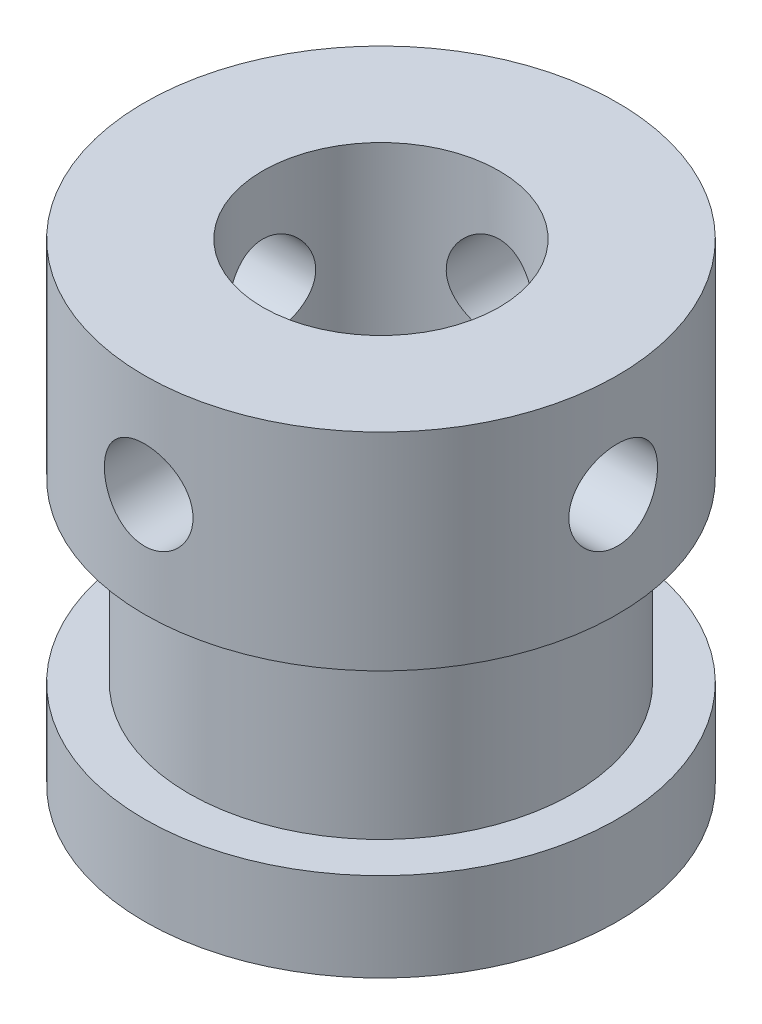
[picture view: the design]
ISO-10303-21;
HEADER;
FILE_DESCRIPTION(('STEP AP214'),'2;1');
FILE_NAME('part.step','',(''),(''),'','','');
FILE_SCHEMA(('AUTOMOTIVE_DESIGN { 1 0 10303 214 1 1 1 1 }'));
ENDSEC;
DATA;
#1=APPLICATION_CONTEXT('core data for automotive mechanical design processes');
#2=APPLICATION_PROTOCOL_DEFINITION('international standard','automotive_design',2000,#1);
#3=PRODUCT_CONTEXT('',#1,'mechanical');
#4=PRODUCT('Part','Part','',(#3));
#5=PRODUCT_RELATED_PRODUCT_CATEGORY('part','',(#4));
#6=PRODUCT_DEFINITION_FORMATION('','',#4);
#7=PRODUCT_DEFINITION_CONTEXT('part definition',#1,'design');
#8=PRODUCT_DEFINITION('design','',#6,#7);
#9=PRODUCT_DEFINITION_SHAPE('','',#8);
#10=(LENGTH_UNIT() NAMED_UNIT(*) SI_UNIT(.MILLI.,.METRE.));
#11=(NAMED_UNIT(*) PLANE_ANGLE_UNIT() SI_UNIT($,.RADIAN.));
#12=(NAMED_UNIT(*) SI_UNIT($,.STERADIAN.) SOLID_ANGLE_UNIT());
#13=UNCERTAINTY_MEASURE_WITH_UNIT(LENGTH_MEASURE(1.E-05),#10,'distance_accuracy_value','');
#14=(GEOMETRIC_REPRESENTATION_CONTEXT(3) GLOBAL_UNCERTAINTY_ASSIGNED_CONTEXT((#13)) GLOBAL_UNIT_ASSIGNED_CONTEXT((#10,
#11,#12)) REPRESENTATION_CONTEXT('',''));
#15=CARTESIAN_POINT('',(0.,0.,0.));
#16=DIRECTION('',(0.,0.,1.));
#17=DIRECTION('',(1.,0.,0.));
#18=AXIS2_PLACEMENT_3D('',#15,#16,#17);
#19=CARTESIAN_POINT('',(0.,16.,0.));
#20=DIRECTION('',(0.,-1.,0.));
#21=DIRECTION('',(0.,0.,-1.));
#22=AXIS2_PLACEMENT_3D('',#19,#20,#21);
#23=CYLINDRICAL_SURFACE('',#22,8.);
#24=CARTESIAN_POINT('',(0.,0.,0.));
#25=DIRECTION('',(0.,1.,0.));
#26=DIRECTION('',(0.,0.,1.));
#27=AXIS2_PLACEMENT_3D('',#24,#25,#26);
#28=CIRCLE('',#27,8.);
#29=CARTESIAN_POINT('',(0.,0.,8.));
#30=VERTEX_POINT('',#29);
#31=EDGE_CURVE('E57',#30,#30,#28,.T.);
#32=ORIENTED_EDGE('',*,*,#31,.T.);
#33=EDGE_LOOP('',(#32));
#34=FACE_BOUND('',#33,.T.);
#35=CARTESIAN_POINT('',(0.,3.,0.));
#36=DIRECTION('',(0.,1.,0.));
#37=DIRECTION('',(0.,0.,1.));
#38=AXIS2_PLACEMENT_3D('',#35,#36,#37);
#39=CIRCLE('',#38,8.);
#40=CARTESIAN_POINT('',(0.,3.,8.));
#41=VERTEX_POINT('',#40);
#42=EDGE_CURVE('E70',#41,#41,#39,.T.);
#43=ORIENTED_EDGE('',*,*,#42,.F.);
#44=EDGE_LOOP('',(#43));
#45=FACE_BOUND('',#44,.T.);
#46=ADVANCED_FACE('F45',(#34,#45),#23,.T.);
#47=CARTESIAN_POINT('',(0.,14.,-8.));
#48=CARTESIAN_POINT('',(-0.0834717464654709,13.9999968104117,-7.99999848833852));
#49=CARTESIAN_POINT('',(-0.166984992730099,13.9930089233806,-7.99868009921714));
#50=CARTESIAN_POINT('',(-0.331658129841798,13.9652600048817,-7.9935478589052));
#51=CARTESIAN_POINT('',(-0.412815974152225,13.9444873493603,-7.98973190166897));
#52=CARTESIAN_POINT('',(-0.570372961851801,13.8898272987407,-7.98003138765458));
#53=CARTESIAN_POINT('',(-0.646776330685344,13.8559517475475,-7.97414869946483));
#54=CARTESIAN_POINT('',(-0.792807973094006,13.7760811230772,-7.96095710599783));
#55=CARTESIAN_POINT('',(-0.862436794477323,13.7300870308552,-7.9536483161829));
#56=CARTESIAN_POINT('',(-0.993783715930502,13.6267002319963,-7.93831336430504));
#57=CARTESIAN_POINT('',(-1.05540895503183,13.5691905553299,-7.93028034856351));
#58=CARTESIAN_POINT('',(-1.16819606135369,13.4446566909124,-7.9144531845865));
#59=CARTESIAN_POINT('',(-1.21935717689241,13.3776318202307,-7.90665905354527));
#60=CARTESIAN_POINT('',(-1.31014998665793,13.235313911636,-7.89212551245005));
#61=CARTESIAN_POINT('',(-1.34968721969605,13.1599596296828,-7.88539493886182));
#62=CARTESIAN_POINT('',(-1.41550524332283,13.0035310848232,-7.87384713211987));
#63=CARTESIAN_POINT('',(-1.44178717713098,12.9224573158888,-7.86902973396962));
#64=CARTESIAN_POINT('',(-1.480050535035,12.7578847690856,-7.8619226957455));
#65=CARTESIAN_POINT('',(-1.49219390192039,12.6744249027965,-7.85960445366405));
#66=CARTESIAN_POINT('',(-1.50233808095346,12.5066226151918,-7.85767197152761));
#67=CARTESIAN_POINT('',(-1.50034016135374,12.4222802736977,-7.8580574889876));
#68=CARTESIAN_POINT('',(-1.48238979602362,12.256280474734,-7.86146292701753));
#69=CARTESIAN_POINT('',(-1.46662149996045,12.1746022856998,-7.86444808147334));
#70=CARTESIAN_POINT('',(-1.42186799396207,12.0150715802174,-7.87266183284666));
#71=CARTESIAN_POINT('',(-1.39288222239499,11.9372192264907,-7.87789052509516));
#72=CARTESIAN_POINT('',(-1.322336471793,11.7870113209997,-7.89003855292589));
#73=CARTESIAN_POINT('',(-1.28070213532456,11.7146915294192,-7.89696783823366));
#74=CARTESIAN_POINT('',(-1.18609368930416,11.5779952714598,-7.91172971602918));
#75=CARTESIAN_POINT('',(-1.13311842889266,11.5136196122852,-7.91956240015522));
#76=CARTESIAN_POINT('',(-1.01633905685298,11.3935750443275,-7.93540001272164));
#77=CARTESIAN_POINT('',(-0.952377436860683,11.3380593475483,-7.94340571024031));
#78=CARTESIAN_POINT('',(-0.815968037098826,11.2385227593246,-7.95857386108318));
#79=CARTESIAN_POINT('',(-0.743520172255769,11.1945019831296,-7.96573630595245));
#80=CARTESIAN_POINT('',(-0.592034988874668,11.11918224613,-7.97842539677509));
#81=CARTESIAN_POINT('',(-0.512989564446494,11.0878992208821,-7.98394999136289));
#82=CARTESIAN_POINT('',(-0.350639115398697,11.0390979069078,-7.99272505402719));
#83=CARTESIAN_POINT('',(-0.267334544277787,11.0215781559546,-7.99597576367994));
#84=CARTESIAN_POINT('',(-0.100148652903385,11.0010139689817,-7.99980360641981));
#85=CARTESIAN_POINT('',(-0.0162940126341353,10.9977596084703,-8.00041950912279));
#86=CARTESIAN_POINT('',(0.150761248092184,11.0052554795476,-7.99901543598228));
#87=CARTESIAN_POINT('',(0.233961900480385,11.0160050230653,-7.99699558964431));
#88=CARTESIAN_POINT('',(0.396681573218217,11.0510290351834,-7.99057111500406));
#89=CARTESIAN_POINT('',(0.476224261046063,11.0751972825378,-7.98618522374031));
#90=CARTESIAN_POINT('',(0.630128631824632,11.1362577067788,-7.97551842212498));
#91=CARTESIAN_POINT('',(0.704489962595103,11.1731507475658,-7.96923738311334));
#92=CARTESIAN_POINT('',(0.846816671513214,11.2590781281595,-7.95538030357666));
#93=CARTESIAN_POINT('',(0.914703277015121,11.3082407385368,-7.94779086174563));
#94=CARTESIAN_POINT('',(1.04133832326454,11.4171381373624,-7.93219343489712));
#95=CARTESIAN_POINT('',(1.10008590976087,11.4768739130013,-7.92418541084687));
#96=CARTESIAN_POINT('',(1.20757295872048,11.6061723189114,-7.9085247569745));
#97=CARTESIAN_POINT('',(1.25616916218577,11.6758549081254,-7.90087825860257));
#98=CARTESIAN_POINT('',(1.34096675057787,11.8225176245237,-7.88692985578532));
#99=CARTESIAN_POINT('',(1.37716859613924,11.8994974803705,-7.8806279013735));
#100=CARTESIAN_POINT('',(1.43594673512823,12.0582058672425,-7.87013024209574));
#101=CARTESIAN_POINT('',(1.45858868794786,12.1399093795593,-7.86592440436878));
#102=CARTESIAN_POINT('',(1.48980679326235,12.3060472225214,-7.86007203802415));
#103=CARTESIAN_POINT('',(1.49838453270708,12.3904812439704,-7.8584252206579));
#104=CARTESIAN_POINT('',(1.50117762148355,12.5582483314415,-7.85789199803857));
#105=CARTESIAN_POINT('',(1.49561895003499,12.641577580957,-7.85896215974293));
#106=CARTESIAN_POINT('',(1.47079175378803,12.8060914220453,-7.86364600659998));
#107=CARTESIAN_POINT('',(1.45152331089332,12.8872760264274,-7.86725967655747));
#108=CARTESIAN_POINT('',(1.39991887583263,13.0450744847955,-7.8766050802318));
#109=CARTESIAN_POINT('',(1.36760735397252,13.1216965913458,-7.88233284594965));
#110=CARTESIAN_POINT('',(1.29085868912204,13.2684682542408,-7.8952638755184));
#111=CARTESIAN_POINT('',(1.24642068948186,13.3386173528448,-7.90246724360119));
#112=CARTESIAN_POINT('',(1.14589487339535,13.4715836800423,-7.91767266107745));
#113=CARTESIAN_POINT('',(1.08964259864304,13.5342754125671,-7.92568505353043));
#114=CARTESIAN_POINT('',(0.967427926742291,13.6494051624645,-7.94152833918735));
#115=CARTESIAN_POINT('',(0.901463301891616,13.7018408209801,-7.94935919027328));
#116=CARTESIAN_POINT('',(0.760984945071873,13.7954109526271,-7.96403975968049));
#117=CARTESIAN_POINT('',(0.686399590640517,13.8364394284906,-7.97088000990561));
#118=CARTESIAN_POINT('',(0.531290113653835,13.9053176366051,-7.98271619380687));
#119=CARTESIAN_POINT('',(0.450771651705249,13.9331797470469,-7.98771385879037));
#120=CARTESIAN_POINT('',(0.308347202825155,13.9692773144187,-7.99428290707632));
#121=CARTESIAN_POINT('',(0.247273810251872,13.9807786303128,-7.99641470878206));
#122=CARTESIAN_POINT('',(0.124141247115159,13.9961410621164,-7.9992737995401));
#123=CARTESIAN_POINT('',(0.06208210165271,14.0000023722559,-8.00000112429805));
#124=CARTESIAN_POINT('',(0.,14.,-8.));
#125=B_SPLINE_CURVE_WITH_KNOTS('',3,(#47,#48,#49,#50,#51,#52,#53,#54,#55,#56,#57,#58,#59,#60,
#61,#62,#63,#64,#65,#66,#67,#68,#69,#70,#71,#72,#73,#74,#75,#76,#77,#78,#79,#80,#81,#82,#83,#84,
#85,#86,#87,#88,#89,#90,#91,#92,#93,#94,#95,#96,#97,#98,#99,#100,#101,#102,#103,#104,#105,#106,
#107,#108,#109,#110,#111,#112,#113,#114,#115,#116,#117,#118,#119,#120,#121,#122,#123,#124),
.UNSPECIFIED.,.T.,.F.,(4,2,2,2,2,2,2,2,2,2,2,2,2,2,2,2,2,2,2,2,2,2,2,2,2,2,2,2,2,2,2,2,2,2,2,2,
2,2,4),(0.,0.250188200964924,0.500587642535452,0.750761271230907,1.00091465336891,
1.2537511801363,1.50660586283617,1.76146190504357,2.01629596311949,2.26818151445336,
2.52004447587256,2.76859000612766,3.01714609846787,3.26719262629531,3.51726454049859,
3.77127768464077,4.02529337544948,4.27962588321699,4.53393136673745,4.78448174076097,
5.03501980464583,5.28360233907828,5.53220175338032,5.78351778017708,6.03485728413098,
6.28953436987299,6.54420198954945,6.79762627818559,7.05102196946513,7.30039252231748,
7.54976158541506,7.79866496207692,8.04758592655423,8.3002336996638,8.55293951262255,
8.80792048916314,9.06266126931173,9.24874344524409,9.43482089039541),.UNSPECIFIED.);
#126=CARTESIAN_POINT('',(0.,14.,-8.));
#127=VERTEX_POINT('',#126);
#128=EDGE_CURVE('E81',#127,#127,#125,.T.);
#129=ORIENTED_EDGE('',*,*,#128,.T.);
#130=EDGE_LOOP('',(#129));
#131=FACE_BOUND('',#130,.T.);
#132=CARTESIAN_POINT('',(1.5,12.5,7.85811682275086));
#133=CARTESIAN_POINT('',(1.49999679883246,12.4165427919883,7.85811843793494));
#134=CARTESIAN_POINT('',(1.49301126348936,12.3330440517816,7.85946079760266));
#135=CARTESIAN_POINT('',(1.46527253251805,12.1684010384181,7.86467851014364));
#136=CARTESIAN_POINT('',(1.44450765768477,12.0872588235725,7.86855601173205));
#137=CARTESIAN_POINT('',(1.38987035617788,11.9297349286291,7.87838976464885));
#138=CARTESIAN_POINT('',(1.35601013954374,11.8533488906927,7.88434407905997));
#139=CARTESIAN_POINT('',(1.27617565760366,11.7073464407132,7.89765826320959));
#140=CARTESIAN_POINT('',(1.23020233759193,11.6377295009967,7.90501802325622));
#141=CARTESIAN_POINT('',(1.12683678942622,11.5063698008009,7.92041614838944));
#142=CARTESIAN_POINT('',(1.06932292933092,11.4447235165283,7.92846116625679));
#143=CARTESIAN_POINT('',(0.944771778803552,11.3318956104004,7.94426457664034));
#144=CARTESIAN_POINT('',(0.877733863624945,11.2807146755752,7.95202295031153));
#145=CARTESIAN_POINT('',(0.735403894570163,11.1899006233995,7.96645017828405));
#146=CARTESIAN_POINT('',(0.660052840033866,11.1503584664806,7.97311028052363));
#147=CARTESIAN_POINT('',(0.503631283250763,11.0845304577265,7.98451608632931));
#148=CARTESIAN_POINT('',(0.422561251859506,11.0582435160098,7.98926194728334));
#149=CARTESIAN_POINT('',(0.258002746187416,11.0199704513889,7.99625755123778));
#150=CARTESIAN_POINT('',(0.174553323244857,11.0078216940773,7.99853565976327));
#151=CARTESIAN_POINT('',(0.00677167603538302,10.9976631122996,8.00043684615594));
#152=CARTESIAN_POINT('',(-0.0775604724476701,10.9996520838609,8.00006015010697));
#153=CARTESIAN_POINT('',(-0.243598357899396,11.0175877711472,7.99671633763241));
#154=CARTESIAN_POINT('',(-0.325323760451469,11.03335936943,7.99378172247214));
#155=CARTESIAN_POINT('',(-0.484947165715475,11.0781356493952,7.98568826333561));
#156=CARTESIAN_POINT('',(-0.56284502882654,11.1071408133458,7.98052933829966));
#157=CARTESIAN_POINT('',(-0.71311006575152,11.1777277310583,7.96851260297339));
#158=CARTESIAN_POINT('',(-0.785443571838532,11.2193794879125,7.96164537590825));
#159=CARTESIAN_POINT('',(-0.922159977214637,11.3140256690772,7.9469714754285));
#160=CARTESIAN_POINT('',(-0.986542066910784,11.3670212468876,7.93916470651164));
#161=CARTESIAN_POINT('',(-1.10656561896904,11.4838157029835,7.92333513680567));
#162=CARTESIAN_POINT('',(-1.16205790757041,11.5477677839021,7.91531085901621));
#163=CARTESIAN_POINT('',(-1.2615517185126,11.6841495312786,7.90006508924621));
#164=CARTESIAN_POINT('',(-1.30555307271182,11.7565793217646,7.89284360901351));
#165=CARTESIAN_POINT('',(-1.38085852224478,11.9080582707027,7.88001893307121));
#166=CARTESIAN_POINT('',(-1.41214093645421,11.9871184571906,7.87441850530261));
#167=CARTESIAN_POINT('',(-1.46093656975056,12.1495011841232,7.86551242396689));
#168=CARTESIAN_POINT('',(-1.47845134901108,12.2328232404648,7.8622065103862));
#169=CARTESIAN_POINT('',(-1.49899672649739,12.4000193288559,7.85831520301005));
#170=CARTESIAN_POINT('',(-1.50224164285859,12.4838661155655,7.85768955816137));
#171=CARTESIAN_POINT('',(-1.49472968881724,12.6509034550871,7.8591219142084));
#172=CARTESIAN_POINT('',(-1.48397351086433,12.7340940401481,7.86117978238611));
#173=CARTESIAN_POINT('',(-1.44894868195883,12.8967529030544,7.86770980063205));
#174=CARTESIAN_POINT('',(-1.4247923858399,12.9762462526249,7.87216186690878));
#175=CARTESIAN_POINT('',(-1.3637722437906,13.1300571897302,7.88296134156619));
#176=CARTESIAN_POINT('',(-1.32690746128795,13.2043743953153,7.88930888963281));
#177=CARTESIAN_POINT('',(-1.2410235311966,13.3466676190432,7.90327577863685));
#178=CARTESIAN_POINT('',(-1.19186899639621,13.4145605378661,7.91090895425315));
#179=CARTESIAN_POINT('',(-1.08298344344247,13.5412120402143,7.926548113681));
#180=CARTESIAN_POINT('',(-1.02325147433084,13.5999698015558,7.93455413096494));
#181=CARTESIAN_POINT('',(-0.893949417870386,13.7074837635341,7.95016624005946));
#182=CARTESIAN_POINT('',(-0.824258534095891,13.756095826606,7.95776555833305));
#183=CARTESIAN_POINT('',(-0.677574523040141,13.8409212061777,7.97159404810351));
#184=CARTESIAN_POINT('',(-0.600581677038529,13.877135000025,7.97782327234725));
#185=CARTESIAN_POINT('',(-0.441877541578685,13.9359200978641,7.98818057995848));
#186=CARTESIAN_POINT('',(-0.360193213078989,13.9585621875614,7.99231954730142));
#187=CARTESIAN_POINT('',(-0.194096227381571,13.9897870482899,7.99807642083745));
#188=CARTESIAN_POINT('',(-0.109683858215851,13.9983712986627,7.99969459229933));
#189=CARTESIAN_POINT('',(0.0580907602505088,14.0011853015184,8.00022227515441));
#190=CARTESIAN_POINT('',(0.141449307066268,13.9956327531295,7.99917286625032));
#191=CARTESIAN_POINT('',(0.306023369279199,13.9708075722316,7.99456866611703));
#192=CARTESIAN_POINT('',(0.387238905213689,13.9515350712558,7.99101389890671));
#193=CARTESIAN_POINT('',(0.545106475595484,13.8999087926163,7.98179837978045));
#194=CARTESIAN_POINT('',(0.621766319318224,13.867578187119,7.97614135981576));
#195=CARTESIAN_POINT('',(0.768605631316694,13.7907795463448,7.96333372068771));
#196=CARTESIAN_POINT('',(0.83878466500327,13.7463106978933,7.95618300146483));
#197=CARTESIAN_POINT('',(0.971755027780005,13.6457485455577,7.94104779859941));
#198=CARTESIAN_POINT('',(1.03442623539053,13.5894979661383,7.93305284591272));
#199=CARTESIAN_POINT('',(1.14951536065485,13.4672954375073,7.91719633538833));
#200=CARTESIAN_POINT('',(1.2019308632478,13.4013412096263,7.90933480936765));
#201=CARTESIAN_POINT('',(1.29547633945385,13.2608735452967,7.89455577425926));
#202=CARTESIAN_POINT('',(1.33649740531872,13.1862865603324,7.88764767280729));
#203=CARTESIAN_POINT('',(1.40536132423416,13.0311742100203,7.87567084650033));
#204=CARTESIAN_POINT('',(1.43321661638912,12.9506545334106,7.87060038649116));
#205=CARTESIAN_POINT('',(1.46929726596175,12.8082477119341,7.86393016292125));
#206=CARTESIAN_POINT('',(1.4807910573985,12.7471942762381,7.86176310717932));
#207=CARTESIAN_POINT('',(1.49614351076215,12.6241015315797,7.85885585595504));
#208=CARTESIAN_POINT('',(1.50000238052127,12.5620622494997,7.85811562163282));
#209=CARTESIAN_POINT('',(1.5,12.5,7.85811682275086));
#210=B_SPLINE_CURVE_WITH_KNOTS('',3,(#132,#133,#134,#135,#136,#137,#138,#139,#140,#141,#142,
#143,#144,#145,#146,#147,#148,#149,#150,#151,#152,#153,#154,#155,#156,#157,#158,#159,#160,#161,
#162,#163,#164,#165,#166,#167,#168,#169,#170,#171,#172,#173,#174,#175,#176,#177,#178,#179,#180,
#181,#182,#183,#184,#185,#186,#187,#188,#189,#190,#191,#192,#193,#194,#195,#196,#197,#198,#199,
#200,#201,#202,#203,#204,#205,#206,#207,#208,#209),.UNSPECIFIED.,.T.,.F.,(4,2,2,2,2,2,2,2,2,2,2,
2,2,2,2,2,2,2,2,2,2,2,2,2,2,2,2,2,2,2,2,2,2,2,2,2,2,2,4),(0.,0.250144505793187,
0.500501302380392,0.750625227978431,1.00072963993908,1.25362335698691,1.50653367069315,
1.76137104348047,2.0161874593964,2.26804275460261,2.51987660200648,2.76855650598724,
3.01724547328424,3.26733691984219,3.51745380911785,3.77140614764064,4.025362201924,
4.27974936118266,4.53410768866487,4.78463248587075,5.03514489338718,5.28358792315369,
5.53204926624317,5.78337862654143,6.03473059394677,6.2894412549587,6.54414210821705,
6.79750269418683,7.0508366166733,7.30029300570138,7.54974700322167,7.79876026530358,
8.0477902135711,8.30038464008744,8.55303847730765,8.80803001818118,9.06278015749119,
9.24880307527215,9.43482092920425),.UNSPECIFIED.);
#211=CARTESIAN_POINT('',(1.5,12.5,7.85811682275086));
#212=VERTEX_POINT('',#211);
#213=EDGE_CURVE('E258',#212,#212,#210,.T.);
#214=ORIENTED_EDGE('',*,*,#213,.T.);
#215=EDGE_LOOP('',(#214));
#216=FACE_BOUND('',#215,.T.);
#217=CARTESIAN_POINT('',(-8.,11.,0.));
#218=CARTESIAN_POINT('',(-7.99999848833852,11.0000031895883,-0.0834717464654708));
#219=CARTESIAN_POINT('',(-7.99868009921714,11.0069910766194,-0.166984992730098));
#220=CARTESIAN_POINT('',(-7.9935478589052,11.0347399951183,-0.331658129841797));
#221=CARTESIAN_POINT('',(-7.98973190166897,11.0555126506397,-0.412815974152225));
#222=CARTESIAN_POINT('',(-7.98003138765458,11.1101727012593,-0.570372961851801));
#223=CARTESIAN_POINT('',(-7.97414869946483,11.1440482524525,-0.646776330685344));
#224=CARTESIAN_POINT('',(-7.96095710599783,11.2239188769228,-0.792807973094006));
#225=CARTESIAN_POINT('',(-7.9536483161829,11.2699129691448,-0.862436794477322));
#226=CARTESIAN_POINT('',(-7.93831336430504,11.3732997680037,-0.993783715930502));
#227=CARTESIAN_POINT('',(-7.93028034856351,11.4308094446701,-1.05540895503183));
#228=CARTESIAN_POINT('',(-7.9144531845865,11.5553433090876,-1.16819606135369));
#229=CARTESIAN_POINT('',(-7.90665905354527,11.6223681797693,-1.21935717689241));
#230=CARTESIAN_POINT('',(-7.89212551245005,11.764686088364,-1.31014998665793));
#231=CARTESIAN_POINT('',(-7.88539493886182,11.8400403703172,-1.34968721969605));
#232=CARTESIAN_POINT('',(-7.87384713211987,11.9964689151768,-1.41550524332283));
#233=CARTESIAN_POINT('',(-7.86902973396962,12.0775426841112,-1.44178717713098));
#234=CARTESIAN_POINT('',(-7.8619226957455,12.2421152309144,-1.480050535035));
#235=CARTESIAN_POINT('',(-7.85960445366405,12.3255750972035,-1.49219390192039));
#236=CARTESIAN_POINT('',(-7.85767197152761,12.4933773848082,-1.50233808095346));
#237=CARTESIAN_POINT('',(-7.8580574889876,12.5777197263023,-1.50034016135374));
#238=CARTESIAN_POINT('',(-7.86146292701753,12.743719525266,-1.48238979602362));
#239=CARTESIAN_POINT('',(-7.86444808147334,12.8253977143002,-1.46662149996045));
#240=CARTESIAN_POINT('',(-7.87266183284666,12.9849284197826,-1.42186799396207));
#241=CARTESIAN_POINT('',(-7.87789052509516,13.0627807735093,-1.39288222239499));
#242=CARTESIAN_POINT('',(-7.89003855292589,13.2129886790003,-1.322336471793));
#243=CARTESIAN_POINT('',(-7.89696783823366,13.2853084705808,-1.28070213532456));
#244=CARTESIAN_POINT('',(-7.91172971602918,13.4220047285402,-1.18609368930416));
#245=CARTESIAN_POINT('',(-7.91956240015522,13.4863803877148,-1.13311842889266));
#246=CARTESIAN_POINT('',(-7.93540001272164,13.6064249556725,-1.01633905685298));
#247=CARTESIAN_POINT('',(-7.94340571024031,13.6619406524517,-0.952377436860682));
#248=CARTESIAN_POINT('',(-7.95857386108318,13.7614772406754,-0.815968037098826));
#249=CARTESIAN_POINT('',(-7.96573630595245,13.8054980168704,-0.743520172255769));
#250=CARTESIAN_POINT('',(-7.97842539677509,13.88081775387,-0.592034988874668));
#251=CARTESIAN_POINT('',(-7.98394999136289,13.9121007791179,-0.512989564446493));
#252=CARTESIAN_POINT('',(-7.99272505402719,13.9609020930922,-0.350639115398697));
#253=CARTESIAN_POINT('',(-7.99597576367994,13.9784218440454,-0.267334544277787));
#254=CARTESIAN_POINT('',(-7.99980360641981,13.9989860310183,-0.100148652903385));
#255=CARTESIAN_POINT('',(-8.00041950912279,14.0022403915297,-0.016294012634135));
#256=CARTESIAN_POINT('',(-7.99901543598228,13.9947445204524,0.150761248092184));
#257=CARTESIAN_POINT('',(-7.99699558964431,13.9839949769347,0.233961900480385));
#258=CARTESIAN_POINT('',(-7.99057111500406,13.9489709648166,0.396681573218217));
#259=CARTESIAN_POINT('',(-7.98618522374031,13.9248027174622,0.476224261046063));
#260=CARTESIAN_POINT('',(-7.97551842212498,13.8637422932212,0.630128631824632));
#261=CARTESIAN_POINT('',(-7.96923738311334,13.8268492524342,0.704489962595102));
#262=CARTESIAN_POINT('',(-7.95538030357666,13.7409218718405,0.846816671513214));
#263=CARTESIAN_POINT('',(-7.94779086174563,13.6917592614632,0.914703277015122));
#264=CARTESIAN_POINT('',(-7.93219343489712,13.5828618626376,1.04133832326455));
#265=CARTESIAN_POINT('',(-7.92418541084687,13.5231260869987,1.10008590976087));
#266=CARTESIAN_POINT('',(-7.9085247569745,13.3938276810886,1.20757295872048));
#267=CARTESIAN_POINT('',(-7.90087825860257,13.3241450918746,1.25616916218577));
#268=CARTESIAN_POINT('',(-7.88692985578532,13.1774823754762,1.34096675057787));
#269=CARTESIAN_POINT('',(-7.8806279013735,13.1005025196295,1.37716859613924));
#270=CARTESIAN_POINT('',(-7.87013024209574,12.9417941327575,1.43594673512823));
#271=CARTESIAN_POINT('',(-7.86592440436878,12.8600906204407,1.45858868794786));
#272=CARTESIAN_POINT('',(-7.86007203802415,12.6939527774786,1.48980679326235));
#273=CARTESIAN_POINT('',(-7.8584252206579,12.6095187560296,1.49838453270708));
#274=CARTESIAN_POINT('',(-7.85789199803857,12.4417516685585,1.50117762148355));
#275=CARTESIAN_POINT('',(-7.85896215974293,12.358422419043,1.49561895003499));
#276=CARTESIAN_POINT('',(-7.86364600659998,12.1939085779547,1.47079175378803));
#277=CARTESIAN_POINT('',(-7.86725967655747,12.1127239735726,1.45152331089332));
#278=CARTESIAN_POINT('',(-7.8766050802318,11.9549255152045,1.39991887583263));
#279=CARTESIAN_POINT('',(-7.88233284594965,11.8783034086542,1.36760735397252));
#280=CARTESIAN_POINT('',(-7.8952638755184,11.7315317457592,1.29085868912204));
#281=CARTESIAN_POINT('',(-7.90246724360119,11.6613826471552,1.24642068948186));
#282=CARTESIAN_POINT('',(-7.91767266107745,11.5284163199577,1.14589487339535));
#283=CARTESIAN_POINT('',(-7.92568505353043,11.4657245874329,1.08964259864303));
#284=CARTESIAN_POINT('',(-7.94152833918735,11.3505948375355,0.967427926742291));
#285=CARTESIAN_POINT('',(-7.94935919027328,11.2981591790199,0.901463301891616));
#286=CARTESIAN_POINT('',(-7.96403975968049,11.2045890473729,0.760984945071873));
#287=CARTESIAN_POINT('',(-7.97088000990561,11.1635605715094,0.686399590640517));
#288=CARTESIAN_POINT('',(-7.98271619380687,11.0946823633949,0.531290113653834));
#289=CARTESIAN_POINT('',(-7.98771385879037,11.0668202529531,0.450771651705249));
#290=CARTESIAN_POINT('',(-7.99428290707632,11.0307226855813,0.308347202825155));
#291=CARTESIAN_POINT('',(-7.99641470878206,11.0192213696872,0.247273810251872));
#292=CARTESIAN_POINT('',(-7.9992737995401,11.0038589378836,0.124141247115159));
#293=CARTESIAN_POINT('',(-8.00000112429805,10.9999976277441,0.0620821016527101));
#294=CARTESIAN_POINT('',(-8.,11.,0.));
#295=B_SPLINE_CURVE_WITH_KNOTS('',3,(#217,#218,#219,#220,#221,#222,#223,#224,#225,#226,#227,
#228,#229,#230,#231,#232,#233,#234,#235,#236,#237,#238,#239,#240,#241,#242,#243,#244,#245,#246,
#247,#248,#249,#250,#251,#252,#253,#254,#255,#256,#257,#258,#259,#260,#261,#262,#263,#264,#265,
#266,#267,#268,#269,#270,#271,#272,#273,#274,#275,#276,#277,#278,#279,#280,#281,#282,#283,#284,
#285,#286,#287,#288,#289,#290,#291,#292,#293,#294),.UNSPECIFIED.,.T.,.F.,(4,2,2,2,2,2,2,2,2,2,2,
2,2,2,2,2,2,2,2,2,2,2,2,2,2,2,2,2,2,2,2,2,2,2,2,2,2,2,4),(0.,0.250188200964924,
0.500587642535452,0.750761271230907,1.00091465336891,1.25375118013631,1.50660586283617,
1.76146190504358,2.01629596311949,2.26818151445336,2.52004447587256,2.76859000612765,
3.01714609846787,3.26719262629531,3.51726454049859,3.77127768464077,4.02529337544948,
4.27962588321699,4.53393136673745,4.78448174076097,5.03501980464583,5.28360233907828,
5.53220175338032,5.78351778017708,6.03485728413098,6.28953436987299,6.54420198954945,
6.79762627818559,7.05102196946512,7.30039252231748,7.54976158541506,7.79866496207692,
8.04758592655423,8.3002336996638,8.55293951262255,8.80792048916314,9.06266126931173,
9.24874344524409,9.4348208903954),.UNSPECIFIED.);
#296=CARTESIAN_POINT('',(-8.,11.,0.));
#297=VERTEX_POINT('',#296);
#298=EDGE_CURVE('E111',#297,#297,#295,.T.);
#299=ORIENTED_EDGE('',*,*,#298,.T.);
#300=EDGE_LOOP('',(#299));
#301=FACE_BOUND('',#300,.T.);
#302=CARTESIAN_POINT('',(7.85811682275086,12.5,-1.5));
#303=CARTESIAN_POINT('',(7.85811843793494,12.4165427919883,-1.49999679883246));
#304=CARTESIAN_POINT('',(7.85946079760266,12.3330440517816,-1.49301126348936));
#305=CARTESIAN_POINT('',(7.86467851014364,12.1684010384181,-1.46527253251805));
#306=CARTESIAN_POINT('',(7.86855601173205,12.0872588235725,-1.44450765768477));
#307=CARTESIAN_POINT('',(7.87838976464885,11.9297349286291,-1.38987035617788));
#308=CARTESIAN_POINT('',(7.88434407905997,11.8533488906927,-1.35601013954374));
#309=CARTESIAN_POINT('',(7.89765826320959,11.7073464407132,-1.27617565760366));
#310=CARTESIAN_POINT('',(7.90501802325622,11.6377295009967,-1.23020233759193));
#311=CARTESIAN_POINT('',(7.92041614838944,11.5063698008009,-1.12683678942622));
#312=CARTESIAN_POINT('',(7.92846116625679,11.4447235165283,-1.06932292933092));
#313=CARTESIAN_POINT('',(7.94426457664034,11.3318956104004,-0.944771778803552));
#314=CARTESIAN_POINT('',(7.95202295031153,11.2807146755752,-0.877733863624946));
#315=CARTESIAN_POINT('',(7.96645017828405,11.1899006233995,-0.735403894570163));
#316=CARTESIAN_POINT('',(7.97311028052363,11.1503584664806,-0.660052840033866));
#317=CARTESIAN_POINT('',(7.98451608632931,11.0845304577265,-0.503631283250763));
#318=CARTESIAN_POINT('',(7.98926194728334,11.0582435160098,-0.422561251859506));
#319=CARTESIAN_POINT('',(7.99625755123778,11.0199704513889,-0.258002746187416));
#320=CARTESIAN_POINT('',(7.99853565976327,11.0078216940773,-0.174553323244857));
#321=CARTESIAN_POINT('',(8.00043684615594,10.9976631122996,-0.00677167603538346));
#322=CARTESIAN_POINT('',(8.00006015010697,10.9996520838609,0.0775604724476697));
#323=CARTESIAN_POINT('',(7.99671633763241,11.0175877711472,0.243598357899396));
#324=CARTESIAN_POINT('',(7.99378172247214,11.03335936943,0.325323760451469));
#325=CARTESIAN_POINT('',(7.98568826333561,11.0781356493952,0.484947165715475));
#326=CARTESIAN_POINT('',(7.98052933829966,11.1071408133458,0.56284502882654));
#327=CARTESIAN_POINT('',(7.96851260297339,11.1777277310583,0.71311006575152));
#328=CARTESIAN_POINT('',(7.96164537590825,11.2193794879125,0.785443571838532));
#329=CARTESIAN_POINT('',(7.9469714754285,11.3140256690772,0.922159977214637));
#330=CARTESIAN_POINT('',(7.93916470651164,11.3670212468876,0.986542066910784));
#331=CARTESIAN_POINT('',(7.92333513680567,11.4838157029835,1.10656561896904));
#332=CARTESIAN_POINT('',(7.91531085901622,11.5477677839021,1.16205790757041));
#333=CARTESIAN_POINT('',(7.90006508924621,11.6841495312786,1.2615517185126));
#334=CARTESIAN_POINT('',(7.89284360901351,11.7565793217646,1.30555307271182));
#335=CARTESIAN_POINT('',(7.88001893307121,11.9080582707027,1.38085852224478));
#336=CARTESIAN_POINT('',(7.87441850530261,11.9871184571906,1.41214093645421));
#337=CARTESIAN_POINT('',(7.86551242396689,12.1495011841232,1.46093656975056));
#338=CARTESIAN_POINT('',(7.8622065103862,12.2328232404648,1.47845134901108));
#339=CARTESIAN_POINT('',(7.85831520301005,12.4000193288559,1.49899672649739));
#340=CARTESIAN_POINT('',(7.85768955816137,12.4838661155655,1.50224164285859));
#341=CARTESIAN_POINT('',(7.8591219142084,12.6509034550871,1.49472968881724));
#342=CARTESIAN_POINT('',(7.86117978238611,12.7340940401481,1.48397351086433));
#343=CARTESIAN_POINT('',(7.86770980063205,12.8967529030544,1.44894868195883));
#344=CARTESIAN_POINT('',(7.87216186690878,12.9762462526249,1.4247923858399));
#345=CARTESIAN_POINT('',(7.88296134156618,13.1300571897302,1.3637722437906));
#346=CARTESIAN_POINT('',(7.88930888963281,13.2043743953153,1.32690746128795));
#347=CARTESIAN_POINT('',(7.90327577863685,13.3466676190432,1.2410235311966));
#348=CARTESIAN_POINT('',(7.91090895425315,13.4145605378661,1.19186899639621));
#349=CARTESIAN_POINT('',(7.926548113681,13.5412120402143,1.08298344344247));
#350=CARTESIAN_POINT('',(7.93455413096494,13.5999698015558,1.02325147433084));
#351=CARTESIAN_POINT('',(7.95016624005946,13.7074837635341,0.893949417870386));
#352=CARTESIAN_POINT('',(7.95776555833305,13.756095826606,0.824258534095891));
#353=CARTESIAN_POINT('',(7.97159404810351,13.8409212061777,0.677574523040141));
#354=CARTESIAN_POINT('',(7.97782327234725,13.877135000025,0.600581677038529));
#355=CARTESIAN_POINT('',(7.98818057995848,13.9359200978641,0.441877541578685));
#356=CARTESIAN_POINT('',(7.99231954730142,13.9585621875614,0.360193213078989));
#357=CARTESIAN_POINT('',(7.99807642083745,13.9897870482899,0.194096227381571));
#358=CARTESIAN_POINT('',(7.99969459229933,13.9983712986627,0.109683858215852));
#359=CARTESIAN_POINT('',(8.00022227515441,14.0011853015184,-0.0580907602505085));
#360=CARTESIAN_POINT('',(7.99917286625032,13.9956327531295,-0.141449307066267));
#361=CARTESIAN_POINT('',(7.99456866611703,13.9708075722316,-0.306023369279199));
#362=CARTESIAN_POINT('',(7.99101389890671,13.9515350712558,-0.387238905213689));
#363=CARTESIAN_POINT('',(7.98179837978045,13.8999087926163,-0.545106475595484));
#364=CARTESIAN_POINT('',(7.97614135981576,13.867578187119,-0.621766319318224));
#365=CARTESIAN_POINT('',(7.96333372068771,13.7907795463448,-0.768605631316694));
#366=CARTESIAN_POINT('',(7.95618300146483,13.7463106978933,-0.83878466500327));
#367=CARTESIAN_POINT('',(7.94104779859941,13.6457485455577,-0.971755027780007));
#368=CARTESIAN_POINT('',(7.93305284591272,13.5894979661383,-1.03442623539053));
#369=CARTESIAN_POINT('',(7.91719633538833,13.4672954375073,-1.14951536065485));
#370=CARTESIAN_POINT('',(7.90933480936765,13.4013412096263,-1.2019308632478));
#371=CARTESIAN_POINT('',(7.89455577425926,13.2608735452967,-1.29547633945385));
#372=CARTESIAN_POINT('',(7.88764767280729,13.1862865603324,-1.33649740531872));
#373=CARTESIAN_POINT('',(7.87567084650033,13.0311742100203,-1.40536132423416));
#374=CARTESIAN_POINT('',(7.87060038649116,12.9506545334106,-1.43321661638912));
#375=CARTESIAN_POINT('',(7.86393016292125,12.8082477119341,-1.46929726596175));
#376=CARTESIAN_POINT('',(7.86176310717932,12.7471942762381,-1.4807910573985));
#377=CARTESIAN_POINT('',(7.85885585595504,12.6241015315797,-1.49614351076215));
#378=CARTESIAN_POINT('',(7.85811562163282,12.5620622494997,-1.50000238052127));
#379=CARTESIAN_POINT('',(7.85811682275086,12.5,-1.5));
#380=B_SPLINE_CURVE_WITH_KNOTS('',3,(#302,#303,#304,#305,#306,#307,#308,#309,#310,#311,#312,
#313,#314,#315,#316,#317,#318,#319,#320,#321,#322,#323,#324,#325,#326,#327,#328,#329,#330,#331,
#332,#333,#334,#335,#336,#337,#338,#339,#340,#341,#342,#343,#344,#345,#346,#347,#348,#349,#350,
#351,#352,#353,#354,#355,#356,#357,#358,#359,#360,#361,#362,#363,#364,#365,#366,#367,#368,#369,
#370,#371,#372,#373,#374,#375,#376,#377,#378,#379),.UNSPECIFIED.,.T.,.F.,(4,2,2,2,2,2,2,2,2,2,2,
2,2,2,2,2,2,2,2,2,2,2,2,2,2,2,2,2,2,2,2,2,2,2,2,2,2,2,4),(0.,0.250144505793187,
0.500501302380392,0.750625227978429,1.00072963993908,1.25362335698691,1.50653367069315,
1.76137104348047,2.0161874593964,2.26804275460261,2.51987660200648,2.76855650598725,
3.01724547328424,3.26733691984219,3.51745380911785,3.77140614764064,4.025362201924,
4.27974936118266,4.53410768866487,4.78463248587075,5.03514489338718,5.28358792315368,
5.53204926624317,5.78337862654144,6.03473059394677,6.28944125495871,6.54414210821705,
6.79750269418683,7.0508366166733,7.30029300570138,7.54974700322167,7.79876026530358,
8.0477902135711,8.30038464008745,8.55303847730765,8.80803001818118,9.06278015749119,
9.24880307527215,9.43482092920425),.UNSPECIFIED.);
#381=CARTESIAN_POINT('',(7.85811682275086,12.5,-1.5));
#382=VERTEX_POINT('',#381);
#383=EDGE_CURVE('E102',#382,#382,#380,.T.);
#384=ORIENTED_EDGE('',*,*,#383,.T.);
#385=EDGE_LOOP('',(#384));
#386=FACE_BOUND('',#385,.T.);
#387=CARTESIAN_POINT('',(0.,9.,0.));
#388=DIRECTION('',(0.,1.,0.));
#389=DIRECTION('',(0.,0.,1.));
#390=AXIS2_PLACEMENT_3D('',#387,#388,#389);
#391=CIRCLE('',#390,8.);
#392=CARTESIAN_POINT('',(0.,9.,8.));
#393=VERTEX_POINT('',#392);
#394=EDGE_CURVE('E69',#393,#393,#391,.T.);
#395=ORIENTED_EDGE('',*,*,#394,.T.);
#396=EDGE_LOOP('',(#395));
#397=FACE_BOUND('',#396,.T.);
#398=CARTESIAN_POINT('',(0.,16.,0.));
#399=DIRECTION('',(0.,1.,0.));
#400=DIRECTION('',(0.,0.,1.));
#401=AXIS2_PLACEMENT_3D('',#398,#399,#400);
#402=CIRCLE('',#401,8.);
#403=CARTESIAN_POINT('',(0.,16.,8.));
#404=VERTEX_POINT('',#403);
#405=EDGE_CURVE('E11',#404,#404,#402,.T.);
#406=ORIENTED_EDGE('',*,*,#405,.F.);
#407=EDGE_LOOP('',(#406));
#408=FACE_BOUND('',#407,.T.);
#409=ADVANCED_FACE('F42',(#131,#216,#301,#386,#397,#408),#23,.T.);
#410=CARTESIAN_POINT('',(0.,16.,0.));
#411=DIRECTION('',(0.,1.,0.));
#412=DIRECTION('',(0.,0.,1.));
#413=AXIS2_PLACEMENT_3D('',#410,#411,#412);
#414=PLANE('',#413);
#415=CARTESIAN_POINT('',(0.,16.,0.));
#416=DIRECTION('',(0.,1.,0.));
#417=DIRECTION('',(0.,0.,1.));
#418=AXIS2_PLACEMENT_3D('',#415,#416,#417);
#419=CIRCLE('',#418,4.);
#420=CARTESIAN_POINT('',(0.,16.,4.));
#421=VERTEX_POINT('',#420);
#422=EDGE_CURVE('E63',#421,#421,#419,.T.);
#423=ORIENTED_EDGE('',*,*,#422,.F.);
#424=EDGE_LOOP('',(#423));
#425=FACE_BOUND('',#424,.T.);
#426=ORIENTED_EDGE('',*,*,#405,.T.);
#427=EDGE_LOOP('',(#426));
#428=FACE_BOUND('',#427,.T.);
#429=ADVANCED_FACE('F135',(#425,#428),#414,.T.);
#430=CARTESIAN_POINT('',(0.,0.,0.));
#431=DIRECTION('',(0.,1.,0.));
#432=DIRECTION('',(0.,0.,1.));
#433=AXIS2_PLACEMENT_3D('',#430,#431,#432);
#434=PLANE('',#433);
#435=CARTESIAN_POINT('',(0.,0.,0.));
#436=DIRECTION('',(0.,1.,0.));
#437=DIRECTION('',(0.,0.,1.));
#438=AXIS2_PLACEMENT_3D('',#435,#436,#437);
#439=CIRCLE('',#438,4.);
#440=CARTESIAN_POINT('',(0.,0.,4.));
#441=VERTEX_POINT('',#440);
#442=EDGE_CURVE('E64',#441,#441,#439,.T.);
#443=ORIENTED_EDGE('',*,*,#442,.T.);
#444=EDGE_LOOP('',(#443));
#445=FACE_BOUND('',#444,.T.);
#446=ORIENTED_EDGE('',*,*,#31,.F.);
#447=EDGE_LOOP('',(#446));
#448=FACE_BOUND('',#447,.T.);
#449=ADVANCED_FACE('F132',(#445,#448),#434,.F.);
#450=CARTESIAN_POINT('',(0.,0.,0.));
#451=DIRECTION('',(0.,1.,0.));
#452=DIRECTION('',(0.,0.,1.));
#453=AXIS2_PLACEMENT_3D('',#450,#451,#452);
#454=CYLINDRICAL_SURFACE('',#453,4.);
#455=CARTESIAN_POINT('',(0.,11.,4.));
#456=CARTESIAN_POINT('',(0.0812350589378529,10.9999970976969,4.00000217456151));
#457=CARTESIAN_POINT('',(0.162450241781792,11.0066197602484,3.99750379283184));
#458=CARTESIAN_POINT('',(0.322453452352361,11.0328281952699,3.98778696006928));
#459=CARTESIAN_POINT('',(0.401241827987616,11.0524121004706,3.98056918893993));
#460=CARTESIAN_POINT('',(0.554060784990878,11.1037530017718,3.96218832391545));
#461=CARTESIAN_POINT('',(0.628100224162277,11.1354865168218,3.9510328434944));
#462=CARTESIAN_POINT('',(0.769799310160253,11.2101064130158,3.92588767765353));
#463=CARTESIAN_POINT('',(0.837457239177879,11.2529957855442,3.91189723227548));
#464=CARTESIAN_POINT('',(0.967346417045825,11.3506125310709,3.88186246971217));
#465=CARTESIAN_POINT('',(1.02927073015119,11.4057302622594,3.86576002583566));
#466=CARTESIAN_POINT('',(1.14324421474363,11.5254104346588,3.83360220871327));
#467=CARTESIAN_POINT('',(1.19529036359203,11.5899757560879,3.81754685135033));
#468=CARTESIAN_POINT('',(1.28998202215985,11.7297174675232,3.78662470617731));
#469=CARTESIAN_POINT('',(1.3321939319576,11.8052043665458,3.77182648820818));
#470=CARTESIAN_POINT('',(1.40318646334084,11.9628483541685,3.74599860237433));
#471=CARTESIAN_POINT('',(1.43197244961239,12.0450027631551,3.73496742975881));
#472=CARTESIAN_POINT('',(1.47408431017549,12.2101167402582,3.71854412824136));
#473=CARTESIAN_POINT('',(1.48799593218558,12.2929050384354,3.71293924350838));
#474=CARTESIAN_POINT('',(1.50179556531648,12.4598161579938,3.70738061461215));
#475=CARTESIAN_POINT('',(1.5016893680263,12.5439384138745,3.70742453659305));
#476=CARTESIAN_POINT('',(1.48790429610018,12.705769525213,3.71297511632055));
#477=CARTESIAN_POINT('',(1.47503808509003,12.7835609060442,3.71815468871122));
#478=CARTESIAN_POINT('',(1.4374416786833,12.9357871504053,3.73284938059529));
#479=CARTESIAN_POINT('',(1.41270969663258,13.0102215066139,3.74236515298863));
#480=CARTESIAN_POINT('',(1.35163748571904,13.1552770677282,3.76485702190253));
#481=CARTESIAN_POINT('',(1.31508648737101,13.2257994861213,3.77789517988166));
#482=CARTESIAN_POINT('',(1.23156073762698,13.359945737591,3.80594210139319));
#483=CARTESIAN_POINT('',(1.18458238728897,13.4235671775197,3.82095154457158));
#484=CARTESIAN_POINT('',(1.07781780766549,13.5466036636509,3.85248038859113));
#485=CARTESIAN_POINT('',(1.01738298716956,13.6054486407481,3.86903347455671));
#486=CARTESIAN_POINT('',(0.887312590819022,13.7123379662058,3.90091728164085));
#487=CARTESIAN_POINT('',(0.817675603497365,13.7603806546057,3.91624781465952));
#488=CARTESIAN_POINT('',(0.66972343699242,13.8449303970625,3.9442639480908));
#489=CARTESIAN_POINT('',(0.591290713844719,13.8812475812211,3.95690498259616));
#490=CARTESIAN_POINT('',(0.428836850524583,13.93998260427,3.97778718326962));
#491=CARTESIAN_POINT('',(0.344818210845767,13.9624066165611,3.98603030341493));
#492=CARTESIAN_POINT('',(0.178375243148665,13.9916227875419,3.99684443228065));
#493=CARTESIAN_POINT('',(0.0961036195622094,13.9991826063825,3.99969369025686));
#494=CARTESIAN_POINT('',(-0.0685724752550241,14.0006910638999,4.00025893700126));
#495=CARTESIAN_POINT('',(-0.150976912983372,13.9946427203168,3.99797606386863));
#496=CARTESIAN_POINT('',(-0.310262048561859,13.9696899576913,3.98871709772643));
#497=CARTESIAN_POINT('',(-0.387233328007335,13.9512884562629,3.98192470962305));
#498=CARTESIAN_POINT('',(-0.53694175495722,13.9028139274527,3.96451477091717));
#499=CARTESIAN_POINT('',(-0.609678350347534,13.872739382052,3.9538967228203));
#500=CARTESIAN_POINT('',(-0.751247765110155,13.8008135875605,3.92949624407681));
#501=CARTESIAN_POINT('',(-0.819903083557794,13.7586422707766,3.91563000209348));
#502=CARTESIAN_POINT('',(-0.949392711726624,13.6640818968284,3.88626671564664));
#503=CARTESIAN_POINT('',(-1.01022412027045,13.6116890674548,3.87076907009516));
#504=CARTESIAN_POINT('',(-1.12603079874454,13.4945958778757,3.8387332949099));
#505=CARTESIAN_POINT('',(-1.18046154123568,13.4293578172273,3.82218696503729));
#506=CARTESIAN_POINT('',(-1.27771050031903,13.2903486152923,3.79078815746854));
#507=CARTESIAN_POINT('',(-1.32052767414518,13.2165767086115,3.77593583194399));
#508=CARTESIAN_POINT('',(-1.39337773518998,13.0619840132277,3.74966829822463));
#509=CARTESIAN_POINT('',(-1.42335685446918,12.9811352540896,3.73826760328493));
#510=CARTESIAN_POINT('',(-1.46907883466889,12.8149902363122,3.72054032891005));
#511=CARTESIAN_POINT('',(-1.48483050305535,12.7296967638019,3.71421061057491));
#512=CARTESIAN_POINT('',(-1.50086347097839,12.5629838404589,3.70775894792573));
#513=CARTESIAN_POINT('',(-1.50207331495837,12.4816673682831,3.70726444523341));
#514=CARTESIAN_POINT('',(-1.49136715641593,12.3200546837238,3.71158412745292));
#515=CARTESIAN_POINT('',(-1.47945239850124,12.2397583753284,3.71639780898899));
#516=CARTESIAN_POINT('',(-1.44355815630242,12.0849527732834,3.73048141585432));
#517=CARTESIAN_POINT('',(-1.41995798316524,12.0103416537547,3.73961085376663));
#518=CARTESIAN_POINT('',(-1.3616969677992,11.8660944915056,3.76121548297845));
#519=CARTESIAN_POINT('',(-1.32703332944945,11.7964597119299,3.77369151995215));
#520=CARTESIAN_POINT('',(-1.24552075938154,11.6601732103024,3.80139723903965));
#521=CARTESIAN_POINT('',(-1.1981283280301,11.5938692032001,3.81673698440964));
#522=CARTESIAN_POINT('',(-1.09334485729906,11.4698584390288,3.84806246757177));
#523=CARTESIAN_POINT('',(-1.03595064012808,11.4121544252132,3.86404840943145));
#524=CARTESIAN_POINT('',(-0.909080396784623,11.3037980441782,3.89590424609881));
#525=CARTESIAN_POINT('',(-0.839118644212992,11.2536962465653,3.91172104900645));
#526=CARTESIAN_POINT('',(-0.691213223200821,11.1659773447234,3.94054514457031));
#527=CARTESIAN_POINT('',(-0.613268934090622,11.1283612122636,3.95355221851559));
#528=CARTESIAN_POINT('',(-0.447999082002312,11.0656231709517,3.9757429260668));
#529=CARTESIAN_POINT('',(-0.360413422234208,11.0411129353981,3.98473657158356));
#530=CARTESIAN_POINT('',(-0.181875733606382,11.0083070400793,3.99686242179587));
#531=CARTESIAN_POINT('',(-0.090925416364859,11.0000032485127,3.99999756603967));
#532=CARTESIAN_POINT('',(0.,11.,4.));
#533=B_SPLINE_CURVE_WITH_KNOTS('',3,(#455,#456,#457,#458,#459,#460,#461,#462,#463,#464,#465,
#466,#467,#468,#469,#470,#471,#472,#473,#474,#475,#476,#477,#478,#479,#480,#481,#482,#483,#484,
#485,#486,#487,#488,#489,#490,#491,#492,#493,#494,#495,#496,#497,#498,#499,#500,#501,#502,#503,
#504,#505,#506,#507,#508,#509,#510,#511,#512,#513,#514,#515,#516,#517,#518,#519,#520,#521,#522,
#523,#524,#525,#526,#527,#528,#529,#530,#531,#532),.UNSPECIFIED.,.T.,.F.,(4,2,2,2,2,2,2,2,2,2,2,
2,2,2,2,2,2,2,2,2,2,2,2,2,2,2,2,2,2,2,2,2,2,2,2,2,2,2,4),(0.,0.24336980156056,0.48670454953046,
0.729571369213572,0.972503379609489,1.22473618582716,1.47704604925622,1.73896674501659,
2.00078269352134,2.25185874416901,2.50283106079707,2.73878345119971,2.97477138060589,
3.21522408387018,3.45575990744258,3.71246153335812,3.96920257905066,4.22991375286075,
4.49050899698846,4.73725019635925,4.9839366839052,5.2211443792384,5.45838293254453,
5.70259221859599,5.94689180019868,6.20536519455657,6.46386178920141,6.72343066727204,
6.98283874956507,7.22558763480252,7.46831350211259,7.70363142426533,7.93900886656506,
8.18672471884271,8.43451941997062,8.69572329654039,8.95694749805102,9.22948515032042,
9.50188601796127),.UNSPECIFIED.);
#534=CARTESIAN_POINT('',(0.,11.,4.));
#535=VERTEX_POINT('',#534);
#536=EDGE_CURVE('E50',#535,#535,#533,.T.);
#537=ORIENTED_EDGE('',*,*,#536,.T.);
#538=EDGE_LOOP('',(#537));
#539=FACE_BOUND('',#538,.T.);
#540=CARTESIAN_POINT('',(1.5,12.5,-3.70809924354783));
#541=CARTESIAN_POINT('',(1.50000304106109,12.4189925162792,-3.70809640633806));
#542=CARTESIAN_POINT('',(1.49341597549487,12.3380050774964,-3.71078260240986));
#543=CARTESIAN_POINT('',(1.46736187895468,12.1784719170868,-3.72116159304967));
#544=CARTESIAN_POINT('',(1.44789523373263,12.099926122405,-3.72885423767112));
#545=CARTESIAN_POINT('',(1.39689657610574,11.9476246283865,-3.748254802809));
#546=CARTESIAN_POINT('',(1.36539347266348,11.8738579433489,-3.7599530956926));
#547=CARTESIAN_POINT('',(1.29131856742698,11.7326281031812,-3.78603134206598));
#548=CARTESIAN_POINT('',(1.24874344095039,11.6651668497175,-3.80041210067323));
#549=CARTESIAN_POINT('',(1.15146661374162,11.5351096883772,-3.83103574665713));
#550=CARTESIAN_POINT('',(1.09630381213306,11.4728714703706,-3.84733341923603));
#551=CARTESIAN_POINT('',(0.976395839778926,11.3582771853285,-3.87949750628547));
#552=CARTESIAN_POINT('',(0.91164863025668,11.3059232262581,-3.89536382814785));
#553=CARTESIAN_POINT('',(0.7716946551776,11.2108604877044,-3.92552873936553));
#554=CARTESIAN_POINT('',(0.696206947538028,11.1685405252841,-3.93975561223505));
#555=CARTESIAN_POINT('',(0.538555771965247,11.0973488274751,-3.96438007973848));
#556=CARTESIAN_POINT('',(0.456394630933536,11.068472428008,-3.97477900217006));
#557=CARTESIAN_POINT('',(0.291489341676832,11.0262421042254,-3.9901869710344));
#558=CARTESIAN_POINT('',(0.208923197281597,11.0122723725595,-3.99540915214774));
#559=CARTESIAN_POINT('',(0.0424643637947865,10.998278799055,-4.0006401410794));
#560=CARTESIAN_POINT('',(-0.0414278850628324,10.9982504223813,-4.00065064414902));
#561=CARTESIAN_POINT('',(-0.203743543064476,11.0117817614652,-3.99559265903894));
#562=CARTESIAN_POINT('',(-0.2822321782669,11.0246692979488,-3.99077541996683));
#563=CARTESIAN_POINT('',(-0.435839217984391,11.0625359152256,-3.97693274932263));
#564=CARTESIAN_POINT('',(-0.510957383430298,11.087515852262,-3.96790701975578));
#565=CARTESIAN_POINT('',(-0.656989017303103,11.1491704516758,-3.94637769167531));
#566=CARTESIAN_POINT('',(-0.727825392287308,11.1860100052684,-3.93382539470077));
#567=CARTESIAN_POINT('',(-0.862486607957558,11.2701920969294,-3.90651310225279));
#568=CARTESIAN_POINT('',(-0.926309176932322,11.3175380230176,-3.8917523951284));
#569=CARTESIAN_POINT('',(-1.04909048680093,11.4246272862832,-3.86052529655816));
#570=CARTESIAN_POINT('',(-1.10754614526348,11.4849339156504,-3.84400963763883));
#571=CARTESIAN_POINT('',(-1.21370395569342,11.6145929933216,-3.81182460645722));
#572=CARTESIAN_POINT('',(-1.261403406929,11.6839477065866,-3.79615544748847));
#573=CARTESIAN_POINT('',(-1.34565611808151,11.8317194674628,-3.76712703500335));
#574=CARTESIAN_POINT('',(-1.38193847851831,11.9103034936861,-3.75382677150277));
#575=CARTESIAN_POINT('',(-1.44056464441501,12.0730962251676,-3.73172438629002));
#576=CARTESIAN_POINT('',(-1.46291620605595,12.1573017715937,-3.72291976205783));
#577=CARTESIAN_POINT('',(-1.49190191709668,12.323975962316,-3.71139597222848));
#578=CARTESIAN_POINT('',(-1.49933521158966,12.4062841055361,-3.70836785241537));
#579=CARTESIAN_POINT('',(-1.50057885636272,12.5710093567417,-3.70786539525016));
#580=CARTESIAN_POINT('',(-1.49439261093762,12.6534264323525,-3.71038967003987));
#581=CARTESIAN_POINT('',(-1.46929733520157,12.8119299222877,-3.72039381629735));
#582=CARTESIAN_POINT('',(-1.45100618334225,12.8881311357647,-3.72763276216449));
#583=CARTESIAN_POINT('',(-1.40299774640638,13.0363479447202,-3.74596487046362));
#584=CARTESIAN_POINT('',(-1.37327812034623,13.1083626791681,-3.75705882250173));
#585=CARTESIAN_POINT('',(-1.30200292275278,13.2491644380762,-3.7823624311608));
#586=CARTESIAN_POINT('',(-1.26004545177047,13.3177292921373,-3.79667328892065));
#587=CARTESIAN_POINT('',(-1.16591317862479,13.447128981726,-3.82662814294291));
#588=CARTESIAN_POINT('',(-1.11373463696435,13.5079609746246,-3.84227262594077));
#589=CARTESIAN_POINT('',(-0.996727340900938,13.6241683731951,-3.87433046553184));
#590=CARTESIAN_POINT('',(-0.931306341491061,13.6789534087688,-3.89072969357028));
#591=CARTESIAN_POINT('',(-0.79179747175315,13.7768383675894,-3.92149874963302));
#592=CARTESIAN_POINT('',(-0.717709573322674,13.8199382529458,-3.93586857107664));
#593=CARTESIAN_POINT('',(-0.563016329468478,13.8929460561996,-3.96094985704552));
#594=CARTESIAN_POINT('',(-0.482434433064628,13.9228991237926,-3.9716738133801));
#595=CARTESIAN_POINT('',(-0.316881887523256,13.9686564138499,-3.98829436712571));
#596=CARTESIAN_POINT('',(-0.231913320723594,13.9844672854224,-3.99419323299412));
#597=CARTESIAN_POINT('',(-0.0653355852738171,14.0007744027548,-4.00028407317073));
#598=CARTESIAN_POINT('',(0.0161807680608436,14.002109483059,-4.00078860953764));
#599=CARTESIAN_POINT('',(0.178226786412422,13.9915848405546,-3.99684889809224));
#600=CARTESIAN_POINT('',(0.258756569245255,13.9797267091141,-3.9924052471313));
#601=CARTESIAN_POINT('',(0.414548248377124,13.9437411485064,-3.97921089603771));
#602=CARTESIAN_POINT('',(0.489890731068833,13.9199200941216,-3.97056791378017));
#603=CARTESIAN_POINT('',(0.635515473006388,13.8609899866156,-3.9498778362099));
#604=CARTESIAN_POINT('',(0.705796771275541,13.8258787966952,-3.93783009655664));
#605=CARTESIAN_POINT('',(0.842540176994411,13.7436860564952,-3.91090618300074));
#606=CARTESIAN_POINT('',(0.908717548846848,13.6961633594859,-3.89593240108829));
#607=CARTESIAN_POINT('',(1.03241734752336,13.5911921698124,-3.86499507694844));
#608=CARTESIAN_POINT('',(1.0899366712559,13.5337401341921,-3.84903118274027));
#609=CARTESIAN_POINT('',(1.19781214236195,13.4069358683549,-3.81688129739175));
#610=CARTESIAN_POINT('',(1.24762999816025,13.3371155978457,-3.8007280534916));
#611=CARTESIAN_POINT('',(1.33484709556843,13.1895841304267,-3.77098325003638));
#612=CARTESIAN_POINT('',(1.37224504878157,13.1118721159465,-3.75739195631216));
#613=CARTESIAN_POINT('',(1.4346588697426,12.9470443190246,-3.73402269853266));
#614=CARTESIAN_POINT('',(1.45906002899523,12.8596656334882,-3.7244380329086));
#615=CARTESIAN_POINT('',(1.49172356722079,12.6815147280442,-3.71147994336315));
#616=CARTESIAN_POINT('',(1.49999659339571,12.59074478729,-3.70810242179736));
#617=CARTESIAN_POINT('',(1.5,12.5,-3.70809924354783));
#618=B_SPLINE_CURVE_WITH_KNOTS('',3,(#540,#541,#542,#543,#544,#545,#546,#547,#548,#549,#550,
#551,#552,#553,#554,#555,#556,#557,#558,#559,#560,#561,#562,#563,#564,#565,#566,#567,#568,#569,
#570,#571,#572,#573,#574,#575,#576,#577,#578,#579,#580,#581,#582,#583,#584,#585,#586,#587,#588,
#589,#590,#591,#592,#593,#594,#595,#596,#597,#598,#599,#600,#601,#602,#603,#604,#605,#606,#607,
#608,#609,#610,#611,#612,#613,#614,#615,#616,#617),.UNSPECIFIED.,.T.,.F.,(4,2,2,2,2,2,2,2,2,2,2,
2,2,2,2,2,2,2,2,2,2,2,2,2,2,2,2,2,2,2,2,2,2,2,2,2,2,2,4),(0.,0.242684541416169,
0.485361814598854,0.72745985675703,0.969630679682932,1.22274652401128,1.47591628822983,
1.73770072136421,1.9993942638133,2.24980018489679,2.50012465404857,2.73806472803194,
2.97602165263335,3.21744131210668,3.45893893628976,3.71456675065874,3.97025867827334,
4.23162592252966,4.49284751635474,4.73965657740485,4.98640395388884,5.22143845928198,
5.45652113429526,5.70041561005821,5.94439948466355,6.20385016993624,6.46330169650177,
6.72185508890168,6.98028685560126,7.22365720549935,7.46699820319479,7.7044027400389,
7.94185223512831,8.18928323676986,8.43680270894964,8.69738599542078,8.95799630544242,
9.23003178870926,9.50188762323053),.UNSPECIFIED.);
#619=CARTESIAN_POINT('',(1.5,12.5,-3.70809924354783));
#620=VERTEX_POINT('',#619);
#621=EDGE_CURVE('E177',#620,#620,#618,.T.);
#622=ORIENTED_EDGE('',*,*,#621,.T.);
#623=EDGE_LOOP('',(#622));
#624=FACE_BOUND('',#623,.T.);
#625=CARTESIAN_POINT('',(-3.70809924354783,12.5,-1.5));
#626=CARTESIAN_POINT('',(-3.70809640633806,12.4189925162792,-1.50000304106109));
#627=CARTESIAN_POINT('',(-3.71078260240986,12.3380050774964,-1.49341597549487));
#628=CARTESIAN_POINT('',(-3.72116159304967,12.1784719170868,-1.46736187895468));
#629=CARTESIAN_POINT('',(-3.72885423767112,12.099926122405,-1.44789523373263));
#630=CARTESIAN_POINT('',(-3.748254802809,11.9476246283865,-1.39689657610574));
#631=CARTESIAN_POINT('',(-3.7599530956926,11.8738579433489,-1.36539347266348));
#632=CARTESIAN_POINT('',(-3.78603134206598,11.7326281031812,-1.29131856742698));
#633=CARTESIAN_POINT('',(-3.80041210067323,11.6651668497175,-1.24874344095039));
#634=CARTESIAN_POINT('',(-3.83103574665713,11.5351096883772,-1.15146661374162));
#635=CARTESIAN_POINT('',(-3.84733341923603,11.4728714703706,-1.09630381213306));
#636=CARTESIAN_POINT('',(-3.87949750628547,11.3582771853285,-0.976395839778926));
#637=CARTESIAN_POINT('',(-3.89536382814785,11.3059232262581,-0.911648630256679));
#638=CARTESIAN_POINT('',(-3.92552873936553,11.2108604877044,-0.7716946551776));
#639=CARTESIAN_POINT('',(-3.93975561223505,11.1685405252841,-0.696206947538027));
#640=CARTESIAN_POINT('',(-3.96438007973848,11.0973488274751,-0.538555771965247));
#641=CARTESIAN_POINT('',(-3.97477900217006,11.068472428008,-0.456394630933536));
#642=CARTESIAN_POINT('',(-3.9901869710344,11.0262421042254,-0.291489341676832));
#643=CARTESIAN_POINT('',(-3.99540915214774,11.0122723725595,-0.208923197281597));
#644=CARTESIAN_POINT('',(-4.0006401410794,10.998278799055,-0.0424643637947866));
#645=CARTESIAN_POINT('',(-4.00065064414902,10.9982504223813,0.0414278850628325));
#646=CARTESIAN_POINT('',(-3.99559265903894,11.0117817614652,0.203743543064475));
#647=CARTESIAN_POINT('',(-3.99077541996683,11.0246692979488,0.2822321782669));
#648=CARTESIAN_POINT('',(-3.97693274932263,11.0625359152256,0.435839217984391));
#649=CARTESIAN_POINT('',(-3.96790701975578,11.087515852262,0.510957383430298));
#650=CARTESIAN_POINT('',(-3.94637769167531,11.1491704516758,0.656989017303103));
#651=CARTESIAN_POINT('',(-3.93382539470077,11.1860100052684,0.727825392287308));
#652=CARTESIAN_POINT('',(-3.90651310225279,11.2701920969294,0.862486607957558));
#653=CARTESIAN_POINT('',(-3.8917523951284,11.3175380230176,0.926309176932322));
#654=CARTESIAN_POINT('',(-3.86052529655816,11.4246272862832,1.04909048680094));
#655=CARTESIAN_POINT('',(-3.84400963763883,11.4849339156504,1.10754614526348));
#656=CARTESIAN_POINT('',(-3.81182460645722,11.6145929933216,1.21370395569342));
#657=CARTESIAN_POINT('',(-3.79615544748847,11.6839477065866,1.261403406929));
#658=CARTESIAN_POINT('',(-3.76712703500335,11.8317194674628,1.34565611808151));
#659=CARTESIAN_POINT('',(-3.75382677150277,11.9103034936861,1.38193847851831));
#660=CARTESIAN_POINT('',(-3.73172438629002,12.0730962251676,1.44056464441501));
#661=CARTESIAN_POINT('',(-3.72291976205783,12.1573017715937,1.46291620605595));
#662=CARTESIAN_POINT('',(-3.71139597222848,12.323975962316,1.49190191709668));
#663=CARTESIAN_POINT('',(-3.70836785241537,12.4062841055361,1.49933521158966));
#664=CARTESIAN_POINT('',(-3.70786539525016,12.5710093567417,1.50057885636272));
#665=CARTESIAN_POINT('',(-3.71038967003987,12.6534264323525,1.49439261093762));
#666=CARTESIAN_POINT('',(-3.72039381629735,12.8119299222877,1.46929733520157));
#667=CARTESIAN_POINT('',(-3.72763276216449,12.8881311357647,1.45100618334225));
#668=CARTESIAN_POINT('',(-3.74596487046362,13.0363479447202,1.40299774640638));
#669=CARTESIAN_POINT('',(-3.75705882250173,13.1083626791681,1.37327812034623));
#670=CARTESIAN_POINT('',(-3.7823624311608,13.2491644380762,1.30200292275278));
#671=CARTESIAN_POINT('',(-3.79667328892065,13.3177292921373,1.26004545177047));
#672=CARTESIAN_POINT('',(-3.82662814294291,13.447128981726,1.16591317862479));
#673=CARTESIAN_POINT('',(-3.84227262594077,13.5079609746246,1.11373463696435));
#674=CARTESIAN_POINT('',(-3.87433046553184,13.6241683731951,0.996727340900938));
#675=CARTESIAN_POINT('',(-3.89072969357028,13.6789534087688,0.931306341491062));
#676=CARTESIAN_POINT('',(-3.92149874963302,13.7768383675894,0.791797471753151));
#677=CARTESIAN_POINT('',(-3.93586857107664,13.8199382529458,0.717709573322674));
#678=CARTESIAN_POINT('',(-3.96094985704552,13.8929460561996,0.563016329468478));
#679=CARTESIAN_POINT('',(-3.9716738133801,13.9228991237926,0.482434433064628));
#680=CARTESIAN_POINT('',(-3.98829436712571,13.9686564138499,0.316881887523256));
#681=CARTESIAN_POINT('',(-3.99419323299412,13.9844672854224,0.231913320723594));
#682=CARTESIAN_POINT('',(-4.00028407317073,14.0007744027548,0.0653355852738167));
#683=CARTESIAN_POINT('',(-4.00078860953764,14.002109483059,-0.016180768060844));
#684=CARTESIAN_POINT('',(-3.99684889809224,13.9915848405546,-0.178226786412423));
#685=CARTESIAN_POINT('',(-3.9924052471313,13.9797267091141,-0.258756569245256));
#686=CARTESIAN_POINT('',(-3.97921089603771,13.9437411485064,-0.414548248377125));
#687=CARTESIAN_POINT('',(-3.97056791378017,13.9199200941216,-0.489890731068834));
#688=CARTESIAN_POINT('',(-3.9498778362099,13.8609899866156,-0.635515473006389));
#689=CARTESIAN_POINT('',(-3.93783009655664,13.8258787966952,-0.705796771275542));
#690=CARTESIAN_POINT('',(-3.91090618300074,13.7436860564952,-0.842540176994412));
#691=CARTESIAN_POINT('',(-3.89593240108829,13.6961633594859,-0.908717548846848));
#692=CARTESIAN_POINT('',(-3.86499507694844,13.5911921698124,-1.03241734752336));
#693=CARTESIAN_POINT('',(-3.84903118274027,13.5337401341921,-1.0899366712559));
#694=CARTESIAN_POINT('',(-3.81688129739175,13.4069358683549,-1.19781214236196));
#695=CARTESIAN_POINT('',(-3.8007280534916,13.3371155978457,-1.24762999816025));
#696=CARTESIAN_POINT('',(-3.77098325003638,13.1895841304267,-1.33484709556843));
#697=CARTESIAN_POINT('',(-3.75739195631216,13.1118721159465,-1.37224504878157));
#698=CARTESIAN_POINT('',(-3.73402269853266,12.9470443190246,-1.4346588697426));
#699=CARTESIAN_POINT('',(-3.7244380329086,12.8596656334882,-1.45906002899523));
#700=CARTESIAN_POINT('',(-3.71147994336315,12.6815147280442,-1.49172356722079));
#701=CARTESIAN_POINT('',(-3.70810242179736,12.59074478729,-1.49999659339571));
#702=CARTESIAN_POINT('',(-3.70809924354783,12.5,-1.5));
#703=B_SPLINE_CURVE_WITH_KNOTS('',3,(#625,#626,#627,#628,#629,#630,#631,#632,#633,#634,#635,
#636,#637,#638,#639,#640,#641,#642,#643,#644,#645,#646,#647,#648,#649,#650,#651,#652,#653,#654,
#655,#656,#657,#658,#659,#660,#661,#662,#663,#664,#665,#666,#667,#668,#669,#670,#671,#672,#673,
#674,#675,#676,#677,#678,#679,#680,#681,#682,#683,#684,#685,#686,#687,#688,#689,#690,#691,#692,
#693,#694,#695,#696,#697,#698,#699,#700,#701,#702),.UNSPECIFIED.,.T.,.F.,(4,2,2,2,2,2,2,2,2,2,2,
2,2,2,2,2,2,2,2,2,2,2,2,2,2,2,2,2,2,2,2,2,2,2,2,2,2,2,4),(0.,0.242684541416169,
0.485361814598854,0.727459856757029,0.969630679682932,1.22274652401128,1.47591628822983,
1.73770072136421,1.9993942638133,2.24980018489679,2.50012465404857,2.73806472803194,
2.97602165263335,3.21744131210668,3.45893893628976,3.71456675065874,3.97025867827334,
4.23162592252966,4.49284751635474,4.73965657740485,4.98640395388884,5.22143845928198,
5.45652113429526,5.70041561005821,5.94439948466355,6.20385016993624,6.46330169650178,
6.72185508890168,6.98028685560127,7.22365720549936,7.4669982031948,7.7044027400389,
7.94185223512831,8.18928323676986,8.43680270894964,8.69738599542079,8.95799630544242,
9.23003178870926,9.50188762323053),.UNSPECIFIED.);
#704=CARTESIAN_POINT('',(-3.70809924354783,12.5,-1.5));
#705=VERTEX_POINT('',#704);
#706=EDGE_CURVE('E84',#705,#705,#703,.T.);
#707=ORIENTED_EDGE('',*,*,#706,.T.);
#708=EDGE_LOOP('',(#707));
#709=FACE_BOUND('',#708,.T.);
#710=CARTESIAN_POINT('',(3.70809924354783,12.5,-1.5));
#711=CARTESIAN_POINT('',(3.70809640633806,12.5810074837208,-1.50000304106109));
#712=CARTESIAN_POINT('',(3.71078260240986,12.6619949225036,-1.49341597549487));
#713=CARTESIAN_POINT('',(3.72116159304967,12.8215280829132,-1.46736187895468));
#714=CARTESIAN_POINT('',(3.72885423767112,12.900073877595,-1.44789523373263));
#715=CARTESIAN_POINT('',(3.748254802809,13.0523753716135,-1.39689657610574));
#716=CARTESIAN_POINT('',(3.7599530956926,13.1261420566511,-1.36539347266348));
#717=CARTESIAN_POINT('',(3.78603134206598,13.2673718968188,-1.29131856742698));
#718=CARTESIAN_POINT('',(3.80041210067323,13.3348331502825,-1.24874344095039));
#719=CARTESIAN_POINT('',(3.83103574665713,13.4648903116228,-1.15146661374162));
#720=CARTESIAN_POINT('',(3.84733341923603,13.5271285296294,-1.09630381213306));
#721=CARTESIAN_POINT('',(3.87949750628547,13.6417228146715,-0.976395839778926));
#722=CARTESIAN_POINT('',(3.89536382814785,13.6940767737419,-0.911648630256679));
#723=CARTESIAN_POINT('',(3.92552873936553,13.7891395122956,-0.7716946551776));
#724=CARTESIAN_POINT('',(3.93975561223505,13.8314594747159,-0.696206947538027));
#725=CARTESIAN_POINT('',(3.96438007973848,13.9026511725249,-0.538555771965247));
#726=CARTESIAN_POINT('',(3.97477900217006,13.931527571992,-0.456394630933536));
#727=CARTESIAN_POINT('',(3.9901869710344,13.9737578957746,-0.291489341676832));
#728=CARTESIAN_POINT('',(3.99540915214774,13.9877276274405,-0.208923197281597));
#729=CARTESIAN_POINT('',(4.0006401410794,14.001721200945,-0.0424643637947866));
#730=CARTESIAN_POINT('',(4.00065064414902,14.0017495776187,0.0414278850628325));
#731=CARTESIAN_POINT('',(3.99559265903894,13.9882182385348,0.203743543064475));
#732=CARTESIAN_POINT('',(3.99077541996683,13.9753307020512,0.2822321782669));
#733=CARTESIAN_POINT('',(3.97693274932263,13.9374640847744,0.435839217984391));
#734=CARTESIAN_POINT('',(3.96790701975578,13.912484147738,0.510957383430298));
#735=CARTESIAN_POINT('',(3.94637769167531,13.8508295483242,0.656989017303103));
#736=CARTESIAN_POINT('',(3.93382539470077,13.8139899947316,0.727825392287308));
#737=CARTESIAN_POINT('',(3.90651310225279,13.7298079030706,0.862486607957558));
#738=CARTESIAN_POINT('',(3.8917523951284,13.6824619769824,0.926309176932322));
#739=CARTESIAN_POINT('',(3.86052529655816,13.5753727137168,1.04909048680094));
#740=CARTESIAN_POINT('',(3.84400963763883,13.5150660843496,1.10754614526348));
#741=CARTESIAN_POINT('',(3.81182460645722,13.3854070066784,1.21370395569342));
#742=CARTESIAN_POINT('',(3.79615544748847,13.3160522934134,1.261403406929));
#743=CARTESIAN_POINT('',(3.76712703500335,13.1682805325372,1.34565611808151));
#744=CARTESIAN_POINT('',(3.75382677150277,13.0896965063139,1.38193847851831));
#745=CARTESIAN_POINT('',(3.73172438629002,12.9269037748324,1.44056464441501));
#746=CARTESIAN_POINT('',(3.72291976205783,12.8426982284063,1.46291620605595));
#747=CARTESIAN_POINT('',(3.71139597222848,12.676024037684,1.49190191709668));
#748=CARTESIAN_POINT('',(3.70836785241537,12.5937158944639,1.49933521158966));
#749=CARTESIAN_POINT('',(3.70786539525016,12.4289906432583,1.50057885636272));
#750=CARTESIAN_POINT('',(3.71038967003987,12.3465735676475,1.49439261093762));
#751=CARTESIAN_POINT('',(3.72039381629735,12.1880700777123,1.46929733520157));
#752=CARTESIAN_POINT('',(3.72763276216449,12.1118688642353,1.45100618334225));
#753=CARTESIAN_POINT('',(3.74596487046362,11.9636520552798,1.40299774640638));
#754=CARTESIAN_POINT('',(3.75705882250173,11.8916373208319,1.37327812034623));
#755=CARTESIAN_POINT('',(3.7823624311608,11.7508355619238,1.30200292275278));
#756=CARTESIAN_POINT('',(3.79667328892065,11.6822707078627,1.26004545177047));
#757=CARTESIAN_POINT('',(3.82662814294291,11.552871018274,1.16591317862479));
#758=CARTESIAN_POINT('',(3.84227262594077,11.4920390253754,1.11373463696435));
#759=CARTESIAN_POINT('',(3.87433046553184,11.3758316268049,0.996727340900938));
#760=CARTESIAN_POINT('',(3.89072969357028,11.3210465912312,0.931306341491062));
#761=CARTESIAN_POINT('',(3.92149874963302,11.2231616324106,0.791797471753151));
#762=CARTESIAN_POINT('',(3.93586857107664,11.1800617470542,0.717709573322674));
#763=CARTESIAN_POINT('',(3.96094985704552,11.1070539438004,0.563016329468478));
#764=CARTESIAN_POINT('',(3.9716738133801,11.0771008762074,0.482434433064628));
#765=CARTESIAN_POINT('',(3.98829436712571,11.0313435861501,0.316881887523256));
#766=CARTESIAN_POINT('',(3.99419323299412,11.0155327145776,0.231913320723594));
#767=CARTESIAN_POINT('',(4.00028407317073,10.9992255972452,0.0653355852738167));
#768=CARTESIAN_POINT('',(4.00078860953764,10.997890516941,-0.016180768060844));
#769=CARTESIAN_POINT('',(3.99684889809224,11.0084151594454,-0.178226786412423));
#770=CARTESIAN_POINT('',(3.9924052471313,11.0202732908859,-0.258756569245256));
#771=CARTESIAN_POINT('',(3.97921089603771,11.0562588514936,-0.414548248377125));
#772=CARTESIAN_POINT('',(3.97056791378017,11.0800799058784,-0.489890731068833));
#773=CARTESIAN_POINT('',(3.9498778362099,11.1390100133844,-0.635515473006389));
#774=CARTESIAN_POINT('',(3.93783009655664,11.1741212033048,-0.705796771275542));
#775=CARTESIAN_POINT('',(3.91090618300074,11.2563139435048,-0.842540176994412));
#776=CARTESIAN_POINT('',(3.89593240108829,11.3038366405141,-0.908717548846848));
#777=CARTESIAN_POINT('',(3.86499507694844,11.4088078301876,-1.03241734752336));
#778=CARTESIAN_POINT('',(3.84903118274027,11.4662598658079,-1.0899366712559));
#779=CARTESIAN_POINT('',(3.81688129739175,11.5930641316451,-1.19781214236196));
#780=CARTESIAN_POINT('',(3.8007280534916,11.6628844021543,-1.24762999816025));
#781=CARTESIAN_POINT('',(3.77098325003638,11.8104158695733,-1.33484709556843));
#782=CARTESIAN_POINT('',(3.75739195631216,11.8881278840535,-1.37224504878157));
#783=CARTESIAN_POINT('',(3.73402269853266,12.0529556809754,-1.4346588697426));
#784=CARTESIAN_POINT('',(3.7244380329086,12.1403343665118,-1.45906002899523));
#785=CARTESIAN_POINT('',(3.71147994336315,12.3184852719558,-1.49172356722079));
#786=CARTESIAN_POINT('',(3.70810242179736,12.40925521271,-1.49999659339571));
#787=CARTESIAN_POINT('',(3.70809924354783,12.5,-1.5));
#788=B_SPLINE_CURVE_WITH_KNOTS('',3,(#710,#711,#712,#713,#714,#715,#716,#717,#718,#719,#720,
#721,#722,#723,#724,#725,#726,#727,#728,#729,#730,#731,#732,#733,#734,#735,#736,#737,#738,#739,
#740,#741,#742,#743,#744,#745,#746,#747,#748,#749,#750,#751,#752,#753,#754,#755,#756,#757,#758,
#759,#760,#761,#762,#763,#764,#765,#766,#767,#768,#769,#770,#771,#772,#773,#774,#775,#776,#777,
#778,#779,#780,#781,#782,#783,#784,#785,#786,#787),.UNSPECIFIED.,.T.,.F.,(4,2,2,2,2,2,2,2,2,2,2,
2,2,2,2,2,2,2,2,2,2,2,2,2,2,2,2,2,2,2,2,2,2,2,2,2,2,2,4),(0.,0.242684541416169,
0.485361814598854,0.727459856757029,0.969630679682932,1.22274652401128,1.47591628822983,
1.73770072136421,1.9993942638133,2.24980018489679,2.50012465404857,2.73806472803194,
2.97602165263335,3.21744131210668,3.45893893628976,3.71456675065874,3.97025867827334,
4.23162592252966,4.49284751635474,4.73965657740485,4.98640395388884,5.22143845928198,
5.45652113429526,5.70041561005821,5.94439948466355,6.20385016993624,6.46330169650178,
6.72185508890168,6.98028685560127,7.22365720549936,7.4669982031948,7.7044027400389,
7.94185223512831,8.18928323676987,8.43680270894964,8.69738599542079,8.95799630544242,
9.23003178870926,9.50188762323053),.UNSPECIFIED.);
#789=CARTESIAN_POINT('',(3.70809924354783,12.5,-1.5));
#790=VERTEX_POINT('',#789);
#791=EDGE_CURVE('E73',#790,#790,#788,.T.);
#792=ORIENTED_EDGE('',*,*,#791,.T.);
#793=EDGE_LOOP('',(#792));
#794=FACE_BOUND('',#793,.T.);
#795=ORIENTED_EDGE('',*,*,#442,.F.);
#796=EDGE_LOOP('',(#795));
#797=FACE_BOUND('',#796,.T.);
#798=ORIENTED_EDGE('',*,*,#422,.T.);
#799=EDGE_LOOP('',(#798));
#800=FACE_BOUND('',#799,.T.);
#801=ADVANCED_FACE('F86',(#539,#624,#709,#794,#797,#800),#454,.F.);
#802=CARTESIAN_POINT('',(0.,9.,0.));
#803=DIRECTION('',(0.,1.,0.));
#804=DIRECTION('',(0.,0.,1.));
#805=AXIS2_PLACEMENT_3D('',#802,#803,#804);
#806=PLANE('',#805);
#807=CARTESIAN_POINT('',(0.,9.,0.));
#808=DIRECTION('',(0.,1.,0.));
#809=DIRECTION('',(0.,0.,1.));
#810=AXIS2_PLACEMENT_3D('',#807,#808,#809);
#811=CIRCLE('',#810,6.5);
#812=CARTESIAN_POINT('',(0.,9.,6.5));
#813=VERTEX_POINT('',#812);
#814=EDGE_CURVE('E71',#813,#813,#811,.T.);
#815=ORIENTED_EDGE('',*,*,#814,.T.);
#816=EDGE_LOOP('',(#815));
#817=FACE_BOUND('',#816,.T.);
#818=ORIENTED_EDGE('',*,*,#394,.F.);
#819=EDGE_LOOP('',(#818));
#820=FACE_BOUND('',#819,.T.);
#821=ADVANCED_FACE('F151',(#817,#820),#806,.F.);
#822=CARTESIAN_POINT('',(0.,3.,0.));
#823=DIRECTION('',(0.,1.,0.));
#824=DIRECTION('',(0.,0.,1.));
#825=AXIS2_PLACEMENT_3D('',#822,#823,#824);
#826=PLANE('',#825);
#827=CARTESIAN_POINT('',(0.,3.,0.));
#828=DIRECTION('',(0.,1.,0.));
#829=DIRECTION('',(0.,0.,1.));
#830=AXIS2_PLACEMENT_3D('',#827,#828,#829);
#831=CIRCLE('',#830,6.5);
#832=CARTESIAN_POINT('',(0.,3.,6.5));
#833=VERTEX_POINT('',#832);
#834=EDGE_CURVE('E122',#833,#833,#831,.T.);
#835=ORIENTED_EDGE('',*,*,#834,.F.);
#836=EDGE_LOOP('',(#835));
#837=FACE_BOUND('',#836,.T.);
#838=ORIENTED_EDGE('',*,*,#42,.T.);
#839=EDGE_LOOP('',(#838));
#840=FACE_BOUND('',#839,.T.);
#841=ADVANCED_FACE('F148',(#837,#840),#826,.T.);
#842=CARTESIAN_POINT('',(0.,9.,0.));
#843=DIRECTION('',(0.,-1.,0.));
#844=DIRECTION('',(0.,0.,-1.));
#845=AXIS2_PLACEMENT_3D('',#842,#843,#844);
#846=CYLINDRICAL_SURFACE('',#845,6.5);
#847=ORIENTED_EDGE('',*,*,#814,.F.);
#848=EDGE_LOOP('',(#847));
#849=FACE_BOUND('',#848,.T.);
#850=ORIENTED_EDGE('',*,*,#834,.T.);
#851=EDGE_LOOP('',(#850));
#852=FACE_BOUND('',#851,.T.);
#853=ADVANCED_FACE('F96',(#849,#852),#846,.T.);
#854=CARTESIAN_POINT('',(-8.,12.5,0.));
#855=DIRECTION('',(1.,0.,0.));
#856=DIRECTION('',(0.,0.,-1.));
#857=AXIS2_PLACEMENT_3D('',#854,#855,#856);
#858=CYLINDRICAL_SURFACE('',#857,1.5);
#859=ORIENTED_EDGE('',*,*,#791,.F.);
#860=EDGE_LOOP('',(#859));
#861=FACE_BOUND('',#860,.T.);
#862=ORIENTED_EDGE('',*,*,#383,.F.);
#863=EDGE_LOOP('',(#862));
#864=FACE_BOUND('',#863,.T.);
#865=ADVANCED_FACE('F94',(#861,#864),#858,.F.);
#866=ORIENTED_EDGE('',*,*,#706,.F.);
#867=EDGE_LOOP('',(#866));
#868=FACE_BOUND('',#867,.T.);
#869=ORIENTED_EDGE('',*,*,#298,.F.);
#870=EDGE_LOOP('',(#869));
#871=FACE_BOUND('',#870,.T.);
#872=ADVANCED_FACE('F89',(#868,#871),#858,.F.);
#873=CARTESIAN_POINT('',(0.,12.5,-8.));
#874=DIRECTION('',(0.,0.,1.));
#875=DIRECTION('',(1.,0.,0.));
#876=AXIS2_PLACEMENT_3D('',#873,#874,#875);
#877=CYLINDRICAL_SURFACE('',#876,1.5);
#878=ORIENTED_EDGE('',*,*,#621,.F.);
#879=EDGE_LOOP('',(#878));
#880=FACE_BOUND('',#879,.T.);
#881=ORIENTED_EDGE('',*,*,#128,.F.);
#882=EDGE_LOOP('',(#881));
#883=FACE_BOUND('',#882,.T.);
#884=ADVANCED_FACE('F93',(#880,#883),#877,.F.);
#885=ORIENTED_EDGE('',*,*,#536,.F.);
#886=EDGE_LOOP('',(#885));
#887=FACE_BOUND('',#886,.T.);
#888=ORIENTED_EDGE('',*,*,#213,.F.);
#889=EDGE_LOOP('',(#888));
#890=FACE_BOUND('',#889,.T.);
#891=ADVANCED_FACE('F242',(#887,#890),#877,.F.);
#892=CLOSED_SHELL('',(#46,#409,#429,#449,#801,#821,#841,#853,#865,#872,#884,#891));
#893=MANIFOLD_SOLID_BREP('B2',#892);
#894=ADVANCED_BREP_SHAPE_REPRESENTATION('',(#18,#893),#14);
#895=SHAPE_DEFINITION_REPRESENTATION(#9,#894);
ENDSEC;
END-ISO-10303-21;
